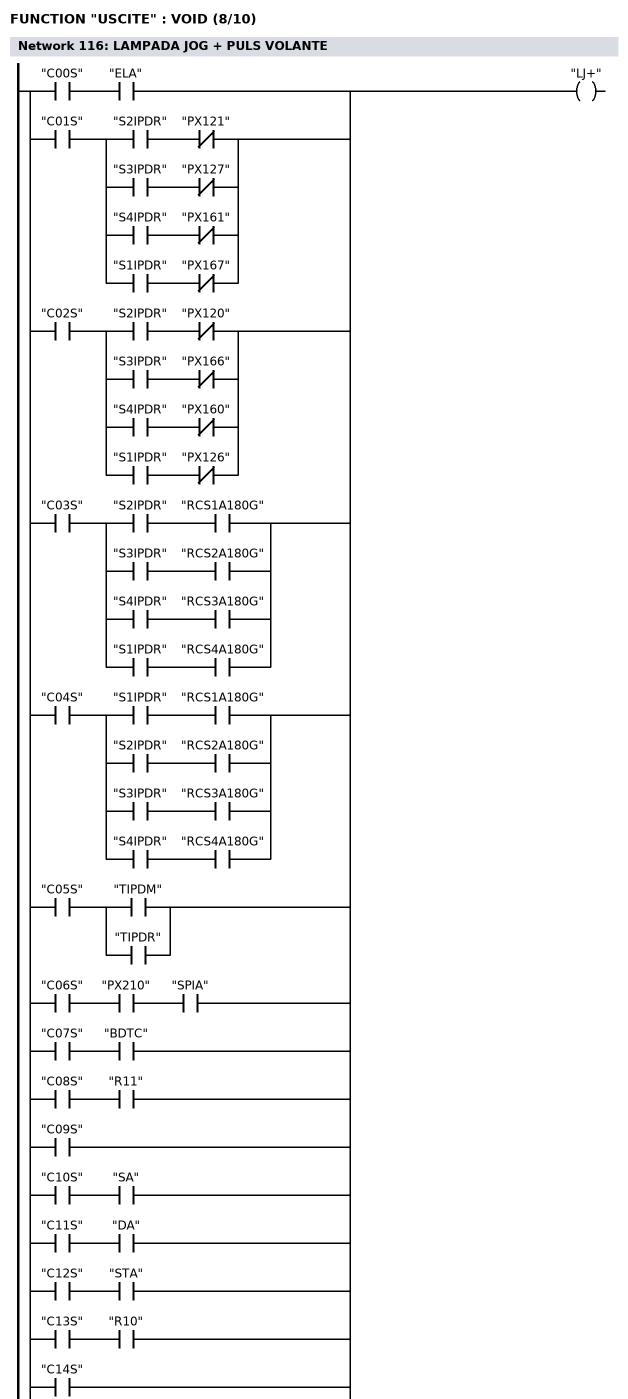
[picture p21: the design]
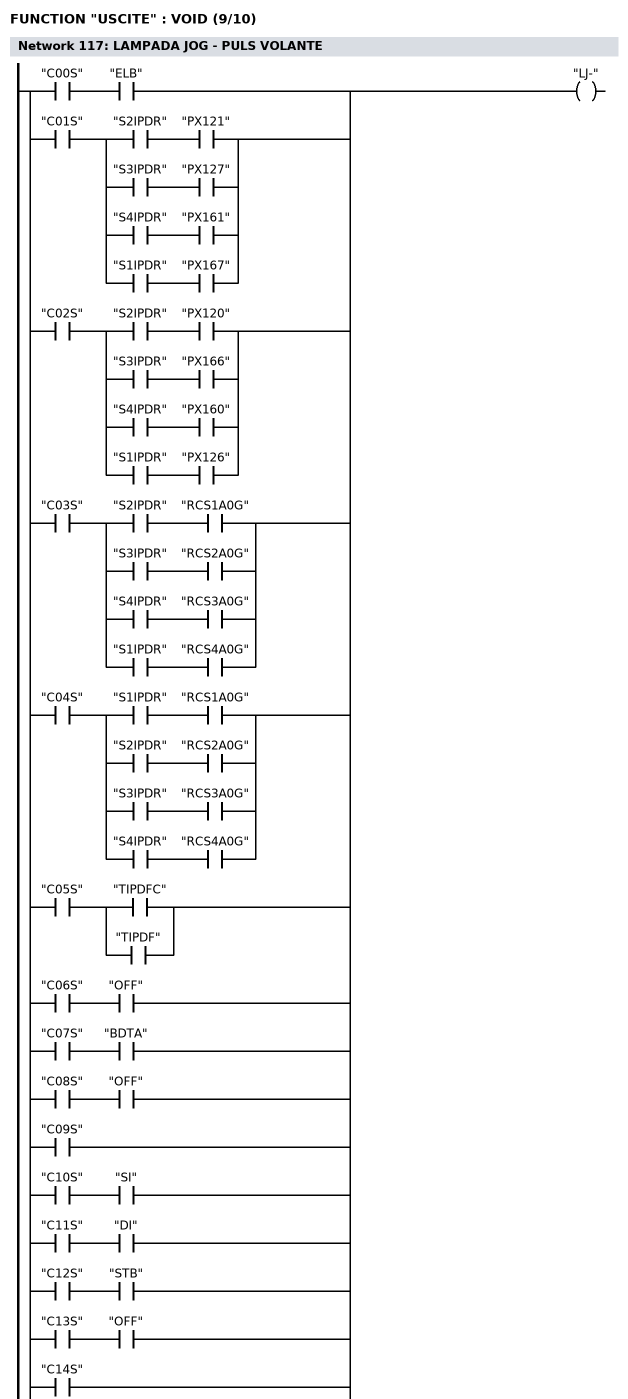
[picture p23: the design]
FUNCTION "USCITE" : VOID
TITLE =USCITE
VERSION : 0.1

BEGIN
NETWORK
TITLE =MARCIA GENERALE

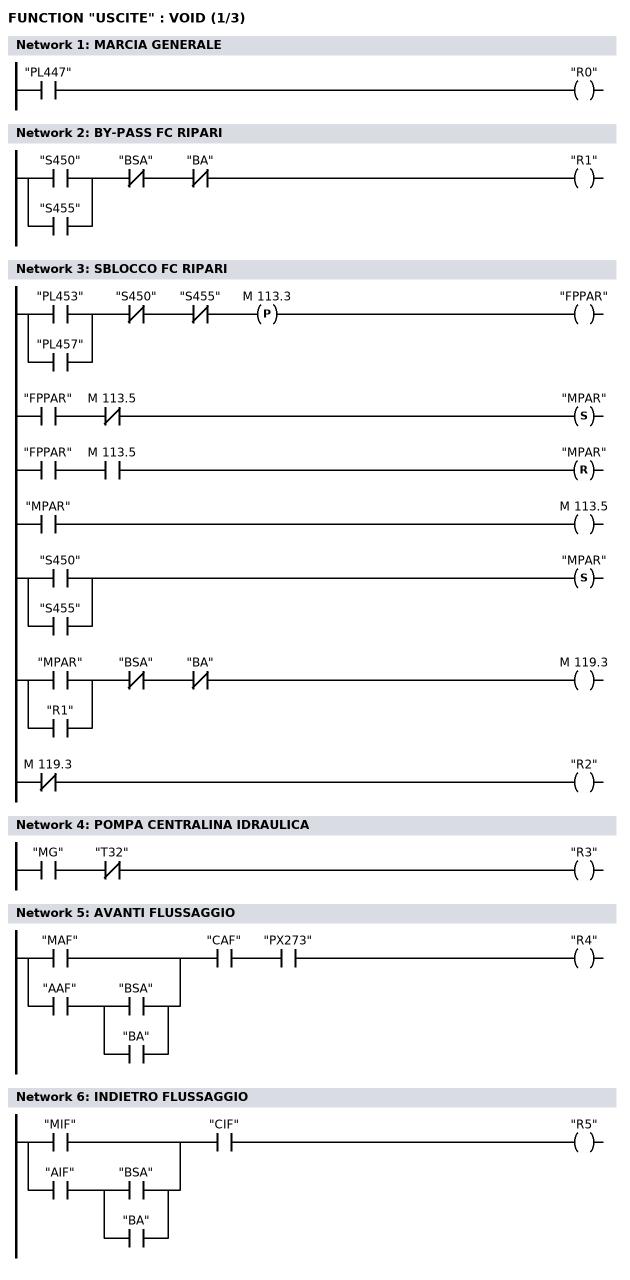
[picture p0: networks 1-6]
      U     "PL447";
      =     "R0";
NETWORK
TITLE =BY-PASS FC RIPARI

      U(    ;
      O     "S450";
      O     "S455";
      )     ;
      UN    "BSA";
      UN    "BA";
      =     "R1";
NETWORK
TITLE =SBLOCCO FC RIPARI

      U(    ;
      U     "PL453";
      O     ;
      U     "PL457";
      )     ;
      UN    "S450";
      UN    "S455";
      FP    M    113.3;
      =     "FPPAR";

      U     "FPPAR";
      UN    M    113.5;
      S     "MPAR";

      U     "FPPAR";
      U     M    113.5;
      R     "MPAR";

      U     "MPAR";
      =     M    113.5;

      U     "S450";
      O     "S455";
      S     "MPAR";

      U(    ;
      U     "MPAR";
      O     ;
      U     "R1";
      )     ;
      UN    "BSA";
      UN    "BA";
      =     M    119.3;
      UN    M    119.3;
      =     "R2";
NETWORK
TITLE =POMPA CENTRALINA IDRAULICA

      U     "MG";
      UN    "T32";
      =     "R3";
NETWORK
TITLE =AVANTI FLUSSAGGIO

      U(    ;
      O     "MAF";
      O     ;
      U     "AAF";
      U(    ;
      O     "BSA";
      O     "BA";
      )     ;
      )     ;
      U     "CAF";
      U     "PX273";
      =     "R4";
NETWORK
TITLE =INDIETRO FLUSSAGGIO

      U(    ;
      O     "MIF";
      O     ;
      U     "AIF";
      U(    ;
      O     "BSA";
      O     "BA";
      )     ;
      )     ;
      U     "CIF";
      =     "R5";
NETWORK
TITLE =AVANTI SPAZZOLATURA

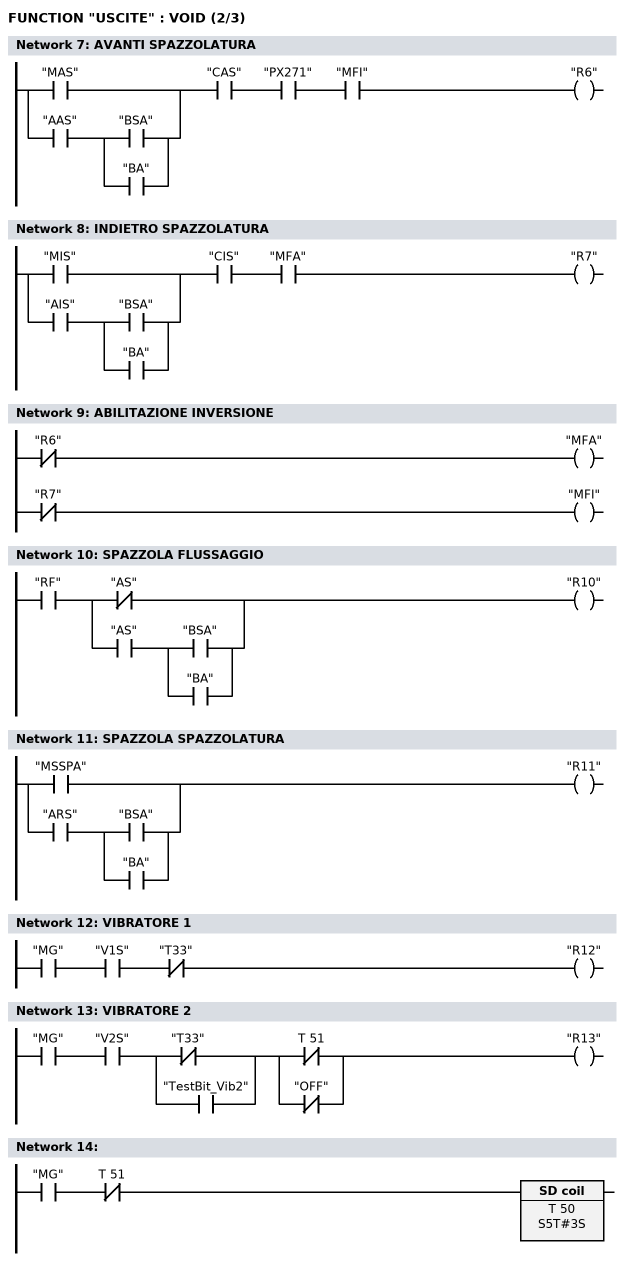
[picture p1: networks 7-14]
      U(    ;
      O     "MAS";
      O     ;
      U     "AAS";
      U(    ;
      O     "BSA";
      O     "BA";
      )     ;
      )     ;
      U     "CAS";
      U     "PX271";
      U     "MFI";
      =     "R6";
NETWORK
TITLE =INDIETRO SPAZZOLATURA

      U(    ;
      O     "MIS";
      O     ;
      U     "AIS";
      U(    ;
      O     "BSA";
      O     "BA";
      )     ;
      )     ;
      U     "CIS";
      U     "MFA";
      =     "R7";
NETWORK
TITLE =ABILITAZIONE INVERSIONE

      UN    "R6";
      =     "MFA";

      UN    "R7";
      =     "MFI";
NETWORK
TITLE =SPAZZOLA FLUSSAGGIO

      U     "RF";
      U(    ;
      ON    "AS";
      O     ;
      U     "AS";
      U(    ;
      O     "BSA";
      O     "BA";
      )     ;
      )     ;
      =     "R10";
NETWORK
TITLE =SPAZZOLA SPAZZOLATURA

      O     "MSSPA";
      O     ;
      U     "ARS";
      U(    ;
      O     "BSA";
      O     "BA";
      )     ;
      =     "R11";
NETWORK
TITLE =VIBRATORE 1

      U     "MG";
      U     "V1S";
      UN    "T33";
      =     "R12";
NETWORK
TITLE =VIBRATORE 2

      U     "MG";
      U     "V2S";
      U(    ;
      ON    "T33";
      O     "TestBit_Vib2";
      )     ;
      U(    ;
      ON    T     51;
      ON    "OFF";
      )     ;
      =     "R13";
NETWORK
TITLE =

      U     "MG";
      UN    T     51;
      L     S5T#3S;
      SE    T     50;
NETWORK
TITLE =

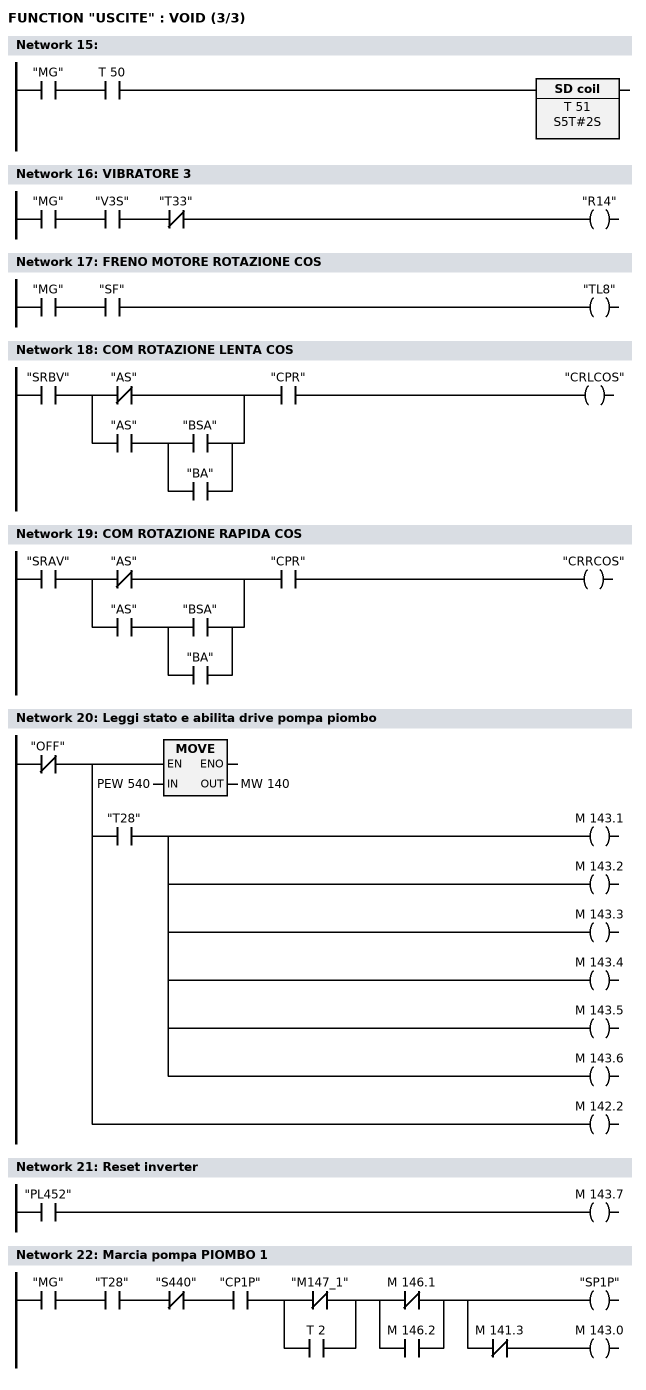
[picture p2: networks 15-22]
      U     "MG";
      U     T     50;
      L     S5T#2S;
      SE    T     51;
NETWORK
TITLE =VIBRATORE 3

      U     "MG";
      U     "V3S";
      UN    "T33";
      =     "R14";
NETWORK
TITLE =FRENO MOTORE ROTAZIONE COS

      U     "MG";
      U     "SF";
      =     "TL8";
NETWORK
TITLE =COM ROTAZIONE LENTA COS

      U     "SRBV";
      U(    ;
      ON    "AS";
      O     ;
      U     "AS";
      U(    ;
      O     "BSA";
      O     "BA";
      )     ;
      )     ;
      U     "CPR";
      =     "CRLCOS";
NETWORK
TITLE =COM ROTAZIONE RAPIDA COS

      U     "SRAV";
      U(    ;
      ON    "AS";
      O     ;
      U     "AS";
      U(    ;
      O     "BSA";
      O     "BA";
      )     ;
      )     ;
      U     "CPR";
      =     "CRRCOS";
NETWORK
TITLE =Leggi stato e abilita drive pompa piombo

      UN    "OFF";
      =     L      0.0;
      U     L      0.0;
      SPBNB _001;
      L     PEW  540;
      T     MW   140;
_001: NOP   0;
      U     L      0.0;
      U     "T28";
      =     M    143.1;
      =     M    143.2;
      =     M    143.3;
      =     M    143.4;
      =     M    143.5;
      =     M    143.6;
      U     L      0.0;
      BLD   102;
      =     M    142.2;
NETWORK
TITLE =Reset inverter

      U     "PL452";
      =     M    143.7;
NETWORK
TITLE =Marcia pompa PIOMBO 1

      U     "MG";
      U     "T28";
      UN    "S440";
      U     "CP1P";
      U(    ;
      ON    "M147_1";
      O     T      2;
      )     ;
      U(    ;
      ON    M    146.1;
      O     M    146.2;
      )     ;
      =     L      0.0;
      U     L      0.0;
      BLD   102;
      =     "SP1P";
      U     L      0.0;
      UN    M    141.3;
      =     M    143.0;
NETWORK
TITLE =Velocita pompa piombo
//Sul ramo di alta velocità della pompa è stato inserita la possibilità di un
//offset (default=0)
      U     "SP1P";
      =     L      0.0;
      U     L      0.0;
      UN    "R43";
      SPBNB _002;
      L     DB32.DBW    0;
      L     12;
      *I    ;
      T     PAW  542;
_002: NOP   0;
      U(    ;
      U     L      0.0;
      U     "R43";
      SPBNB _003;
      L     DB32.DBW    2;
      L     0;
      +I    ;
      T     MW   134;
      UN    OV;
      SAVE  ;
      CLR   ;
_003: U     BIE;
      )     ;
      SPBNB _004;
      L     MW   134;
      L     12;
      *I    ;
      T     PAW  542;
_004: NOP   0;
      U     L      0.0;
      NOT   ;
      SPBNB _005;
      L     0;
      T     PAW  542;
_005: NOP   0;
NETWORK
TITLE =Scrivi comandi pompa piombo

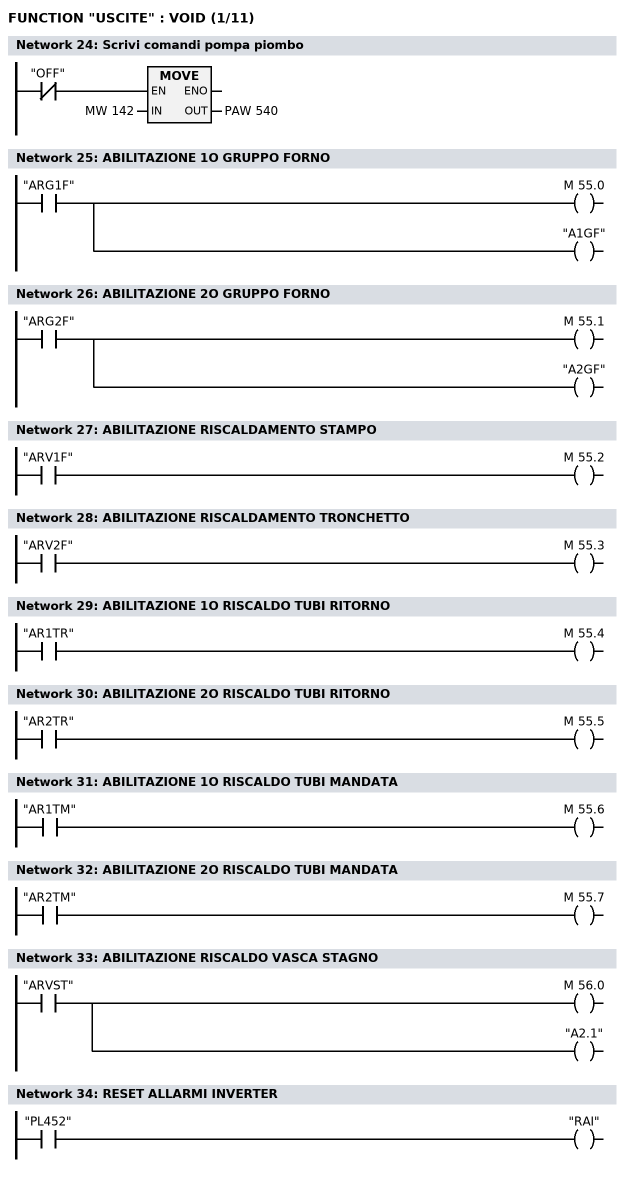
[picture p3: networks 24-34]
      UN    "OFF";
      SPBNB _006;
      L     MW   142;
      T     PAW  540;
_006: NOP   0;
NETWORK
TITLE =ABILITAZIONE 1O GRUPPO FORNO

      U     "ARG1F";
      =     M     55.0;
      =     "A1GF";
NETWORK
TITLE =ABILITAZIONE 2O GRUPPO FORNO

      U     "ARG2F";
      =     M     55.1;
      =     "A2GF";
NETWORK
TITLE =ABILITAZIONE RISCALDAMENTO STAMPO

      U     "ARV1F";
      =     M     55.2;
NETWORK
TITLE =ABILITAZIONE RISCALDAMENTO TRONCHETTO

      U     "ARV2F";
      =     M     55.3;
NETWORK
TITLE =ABILITAZIONE 1O RISCALDO TUBI RITORNO

      U     "AR1TR";
      =     M     55.4;
NETWORK
TITLE =ABILITAZIONE 2O RISCALDO TUBI RITORNO

      U     "AR2TR";
      =     M     55.5;
NETWORK
TITLE =ABILITAZIONE 1O RISCALDO TUBI MANDATA

      U     "AR1TM";
      =     M     55.6;
NETWORK
TITLE =ABILITAZIONE 2O RISCALDO TUBI MANDATA

      U     "AR2TM";
      =     M     55.7;
NETWORK
TITLE =ABILITAZIONE RISCALDO VASCA STAGNO

      U     "ARVST";
      =     M     56.0;
      =     "A2.1";
NETWORK
TITLE =RESET ALLARMI INVERTER

      U     "PL452";
      =     "RAI";
NETWORK
TITLE =MEM ABILITAZIONE ASSI

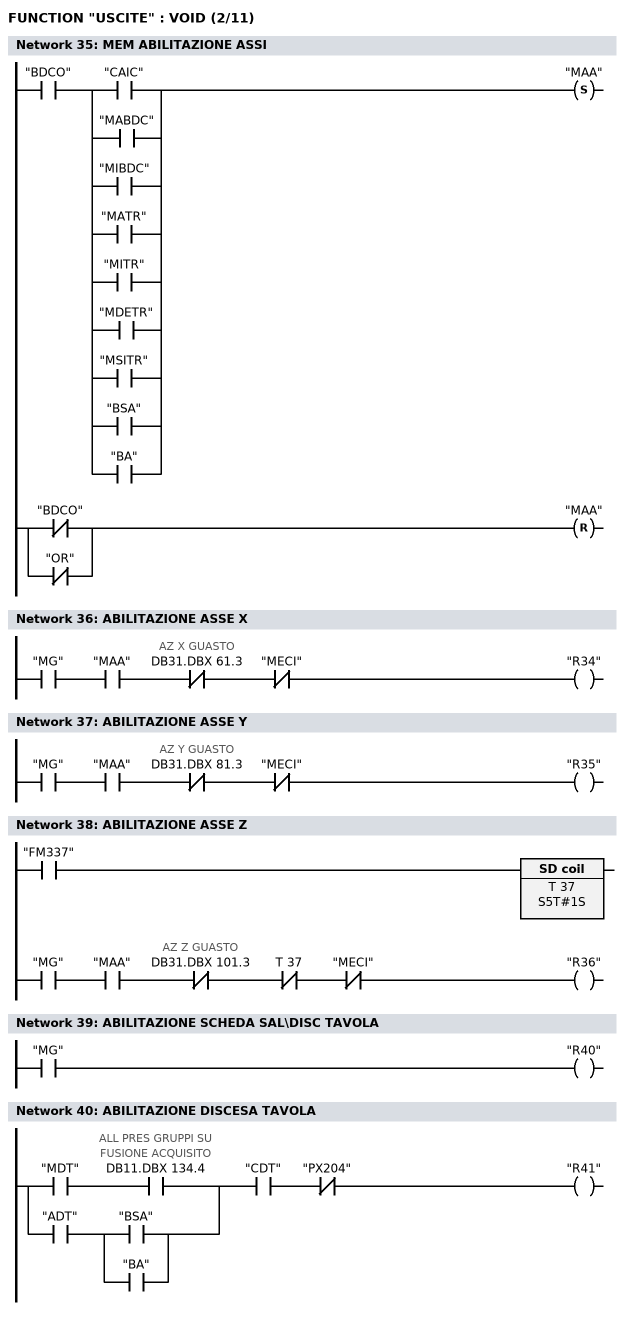
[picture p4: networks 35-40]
      U     "BDCO";
      U(    ;
      U     "CAIC";
      O     "MABDC";
      O     "MIBDC";
      O     "MATR";
      O     "MITR";
      O     "MDETR";
      O     "MSITR";
      O     "BSA";
      O     "BA";
      )     ;
      S     "MAA";

      UN    "BDCO";
      ON    "OR";
      R     "MAA";
NETWORK
TITLE =ABILITAZIONE ASSE X

      U     "MG";
      U     "MAA";
      UN    DB31.DBX   61.3; // AZ X GUASTO
      UN    "MECI";
      =     "R34";
NETWORK
TITLE =ABILITAZIONE ASSE Y

      U     "MG";
      U     "MAA";
      UN    DB31.DBX   81.3; // AZ Y GUASTO
      UN    "MECI";
      =     "R35";
NETWORK
TITLE =ABILITAZIONE ASSE Z

      U     "FM337";
      L     S5T#1S;
      SE    T     37;

      U     "MG";
      U     "MAA";
      UN    DB31.DBX  101.3; // AZ Z GUASTO
      UN    T     37;
      UN    "MECI";
      =     "R36";
NETWORK
TITLE =ABILITAZIONE SCHEDA SAL\DISC TAVOLA

      U     "MG";
      =     "R40";
NETWORK
TITLE =ABILITAZIONE DISCESA TAVOLA

      U(    ;
      U     "MDT";
      U     DB11.DBX  134.4; // ALL PRES GRUPPI SU FUSIONE ACQUISITO
      O     ;
      U     "ADT";
      U(    ;
      O     "BSA";
      O     "BA";
      )     ;
      )     ;
      U     "CDT";
      UN    "PX204";
      =     "R41";
NETWORK
TITLE =ABILITAZIONE SALITA TAVOLA

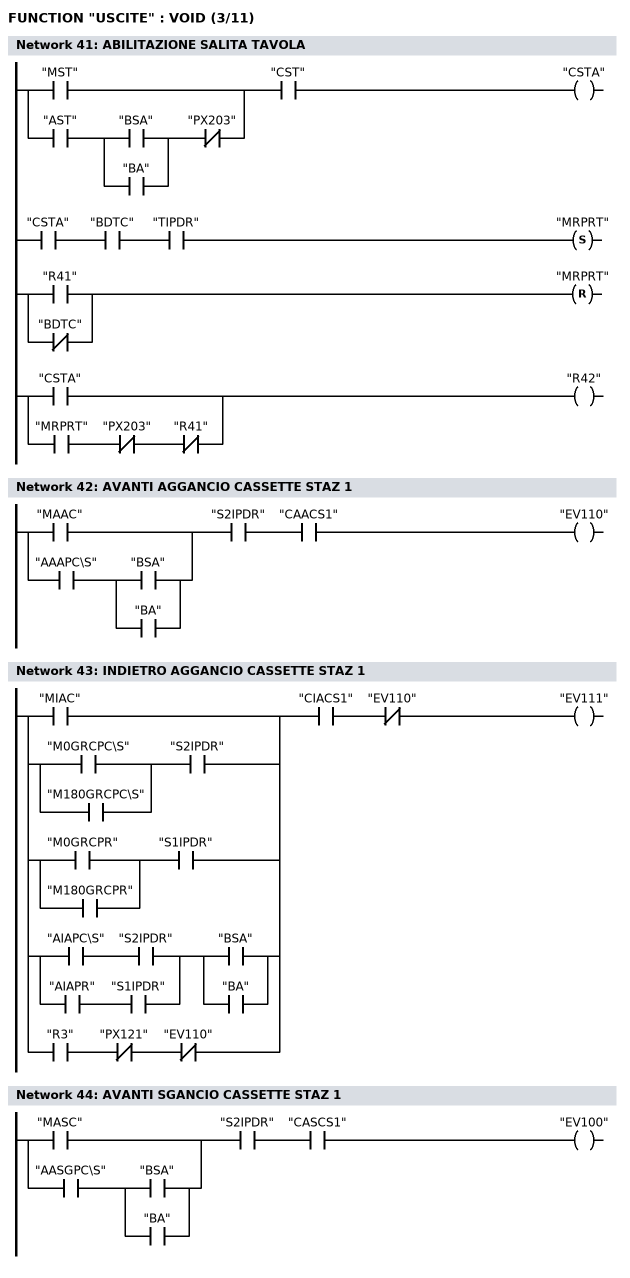
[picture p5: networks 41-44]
      U(    ;
      U     "MST";
      O     ;
      U     "AST";
      U(    ;
      U     "BSA";
      O     "BA";
      )     ;
      UN    "PX203";
      )     ;
      U     "CST";
      =     "CSTA";

      U     "CSTA";
      U     "BDTC";
      U     "TIPDR";
      S     "MRPRT";

      U     "R41";
      ON    "BDTC";
      R     "MRPRT";

      U     "CSTA";
      O     ;
      U     "MRPRT";
      UN    "PX203";
      UN    "R41";
      =     "R42";
NETWORK
TITLE =AVANTI AGGANCIO CASSETTE STAZ 1

      U(    ;
      O     "MAAC";
      O     ;
      U     "AAAPC\S";
      U(    ;
      O     "BSA";
      O     "BA";
      )     ;
      )     ;
      U     "S2IPDR";
      U     "CAACS1";
      =     "EV110";
NETWORK
TITLE =INDIETRO AGGANCIO CASSETTE STAZ 1

      U(    ;
      O     "MIAC";
      O     ;
      U(    ;
      O     "M0GRCPC\S";
      O     "M180GRCPC\S";
      )     ;
      U     "S2IPDR";
      O     ;
      U(    ;
      O     "M0GRCPR";
      O     "M180GRCPR";
      )     ;
      U     "S1IPDR";
      O     ;
      U(    ;
      U     "AIAPC\S";
      U     "S2IPDR";
      O     ;
      U     "AIAPR";
      U     "S1IPDR";
      )     ;
      U(    ;
      O     "BSA";
      O     "BA";
      )     ;
      O     ;
      U     "R3";
      UN    "PX121";
      UN    "EV110";
      )     ;
      U     "CIACS1";
      UN    "EV110";
      =     "EV111";
NETWORK
TITLE =AVANTI SGANCIO CASSETTE STAZ 1

      U(    ;
      O     "MASC";
      O     ;
      U     "AASGPC\S";
      U(    ;
      O     "BSA";
      O     "BA";
      )     ;
      )     ;
      U     "S2IPDR";
      U     "CASCS1";
      =     "EV100";
NETWORK
TITLE =INDIETRO SGANCIO CASSETTE STAZ 1

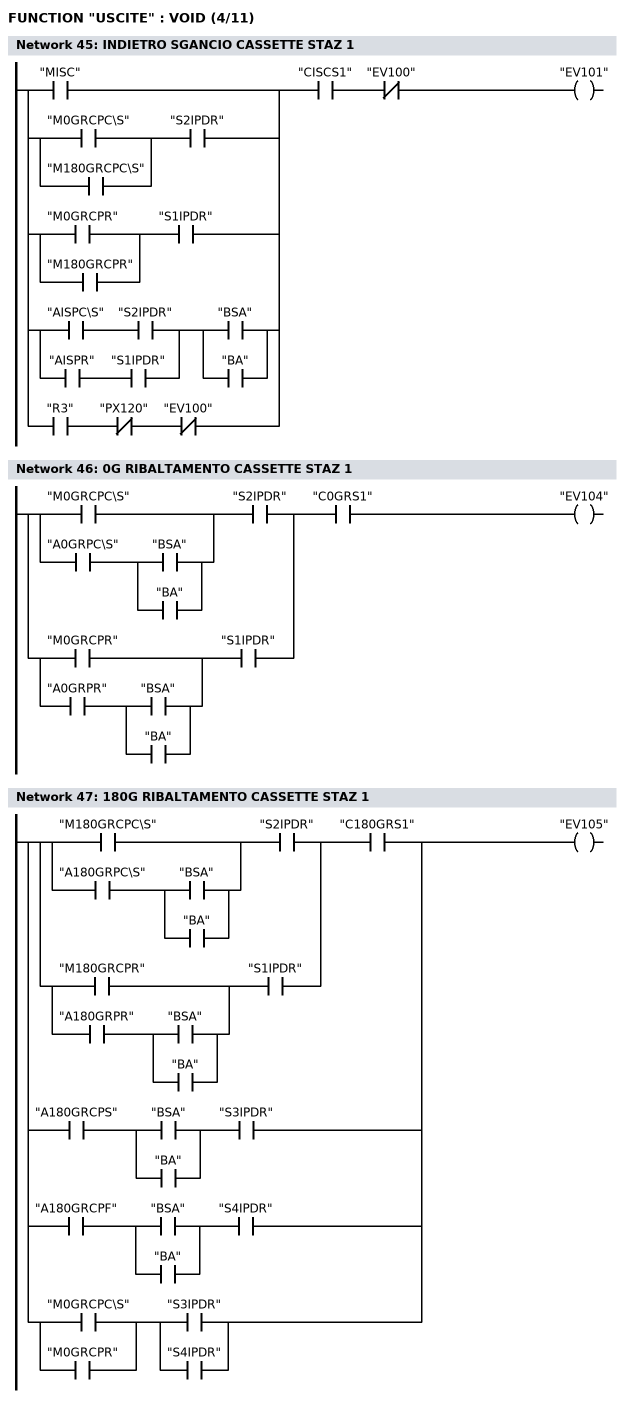
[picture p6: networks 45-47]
      U(    ;
      O     "MISC";
      O     ;
      U(    ;
      O     "M0GRCPC\S";
      O     "M180GRCPC\S";
      )     ;
      U     "S2IPDR";
      O     ;
      U(    ;
      O     "M0GRCPR";
      O     "M180GRCPR";
      )     ;
      U     "S1IPDR";
      O     ;
      U(    ;
      U     "AISPC\S";
      U     "S2IPDR";
      O     ;
      U     "AISPR";
      U     "S1IPDR";
      )     ;
      U(    ;
      O     "BSA";
      O     "BA";
      )     ;
      O     ;
      U     "R3";
      UN    "PX120";
      UN    "EV100";
      )     ;
      U     "CISCS1";
      UN    "EV100";
      =     "EV101";
NETWORK
TITLE =0G RIBALTAMENTO CASSETTE STAZ 1

      U(    ;
      U(    ;
      O     "M0GRCPC\S";
      O     ;
      U     "A0GRPC\S";
      U(    ;
      O     "BSA";
      O     "BA";
      )     ;
      )     ;
      U     "S2IPDR";
      O     ;
      U(    ;
      O     "M0GRCPR";
      O     ;
      U     "A0GRPR";
      U(    ;
      O     "BSA";
      O     "BA";
      )     ;
      )     ;
      U     "S1IPDR";
      )     ;
      U     "C0GRS1";
      =     "EV104";
NETWORK
TITLE =180G RIBALTAMENTO CASSETTE STAZ 1

      U(    ;
      U(    ;
      O     "M180GRCPC\S";
      O     ;
      U     "A180GRPC\S";
      U(    ;
      O     "BSA";
      O     "BA";
      )     ;
      )     ;
      U     "S2IPDR";
      O     ;
      U(    ;
      O     "M180GRCPR";
      O     ;
      U     "A180GRPR";
      U(    ;
      O     "BSA";
      O     "BA";
      )     ;
      )     ;
      U     "S1IPDR";
      )     ;
      U     "C180GRS1";
      O     ;
      U     "A180GRCPS";
      U(    ;
      O     "BSA";
      O     "BA";
      )     ;
      U     "S3IPDR";
      O     ;
      U     "A180GRCPF";
      U(    ;
      O     "BSA";
      O     "BA";
      )     ;
      U     "S4IPDR";
      O     ;
      U(    ;
      O     "M0GRCPC\S";
      O     "M0GRCPR";
      )     ;
      U(    ;
      O     "S3IPDR";
      O     "S4IPDR";
      )     ;
      =     "EV105";
NETWORK
TITLE =AVANTI AGGANCIO CASSETTE STAZ 2

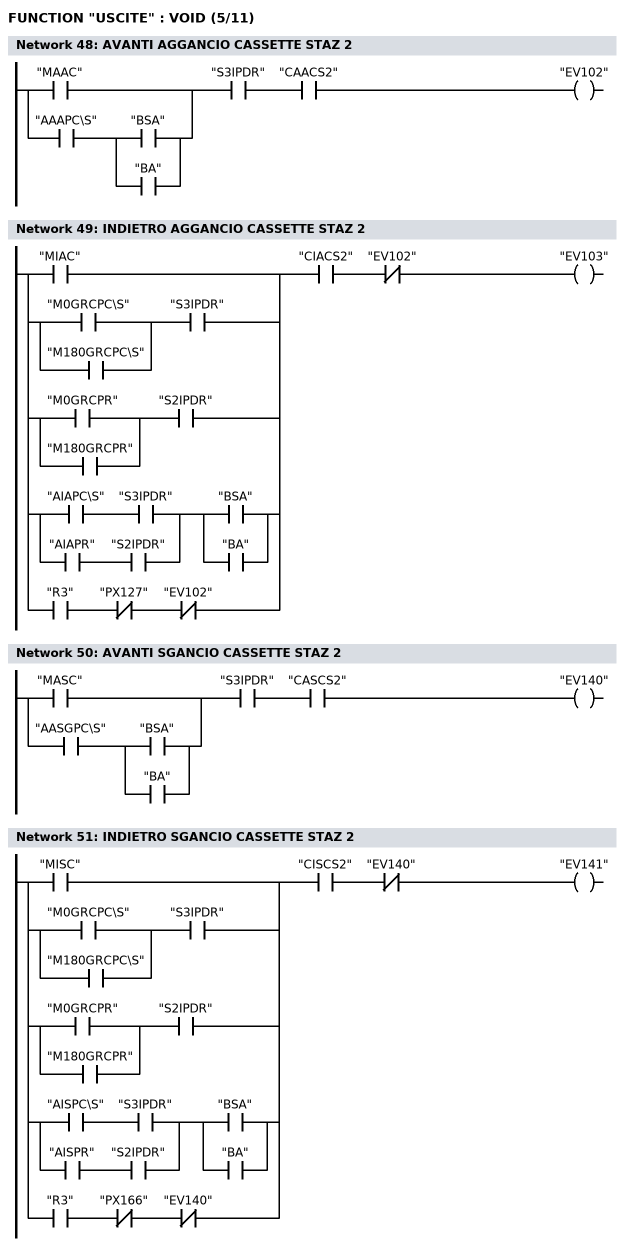
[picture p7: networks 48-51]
      U(    ;
      O     "MAAC";
      O     ;
      U     "AAAPC\S";
      U(    ;
      O     "BSA";
      O     "BA";
      )     ;
      )     ;
      U     "S3IPDR";
      U     "CAACS2";
      =     "EV102";
NETWORK
TITLE =INDIETRO AGGANCIO CASSETTE STAZ 2

      U(    ;
      O     "MIAC";
      O     ;
      U(    ;
      O     "M0GRCPC\S";
      O     "M180GRCPC\S";
      )     ;
      U     "S3IPDR";
      O     ;
      U(    ;
      O     "M0GRCPR";
      O     "M180GRCPR";
      )     ;
      U     "S2IPDR";
      O     ;
      U(    ;
      U     "AIAPC\S";
      U     "S3IPDR";
      O     ;
      U     "AIAPR";
      U     "S2IPDR";
      )     ;
      U(    ;
      O     "BSA";
      O     "BA";
      )     ;
      O     ;
      U     "R3";
      UN    "PX127";
      UN    "EV102";
      )     ;
      U     "CIACS2";
      UN    "EV102";
      =     "EV103";
NETWORK
TITLE =AVANTI SGANCIO CASSETTE STAZ 2

      U(    ;
      O     "MASC";
      O     ;
      U     "AASGPC\S";
      U(    ;
      O     "BSA";
      O     "BA";
      )     ;
      )     ;
      U     "S3IPDR";
      U     "CASCS2";
      =     "EV140";
NETWORK
TITLE =INDIETRO SGANCIO CASSETTE STAZ 2

      U(    ;
      O     "MISC";
      O     ;
      U(    ;
      O     "M0GRCPC\S";
      O     "M180GRCPC\S";
      )     ;
      U     "S3IPDR";
      O     ;
      U(    ;
      O     "M0GRCPR";
      O     "M180GRCPR";
      )     ;
      U     "S2IPDR";
      O     ;
      U(    ;
      U     "AISPC\S";
      U     "S3IPDR";
      O     ;
      U     "AISPR";
      U     "S2IPDR";
      )     ;
      U(    ;
      O     "BSA";
      O     "BA";
      )     ;
      O     ;
      U     "R3";
      UN    "PX166";
      UN    "EV140";
      )     ;
      U     "CISCS2";
      UN    "EV140";
      =     "EV141";
NETWORK
TITLE =0G RIBALTAMENTO CASSETTE STAZ 2

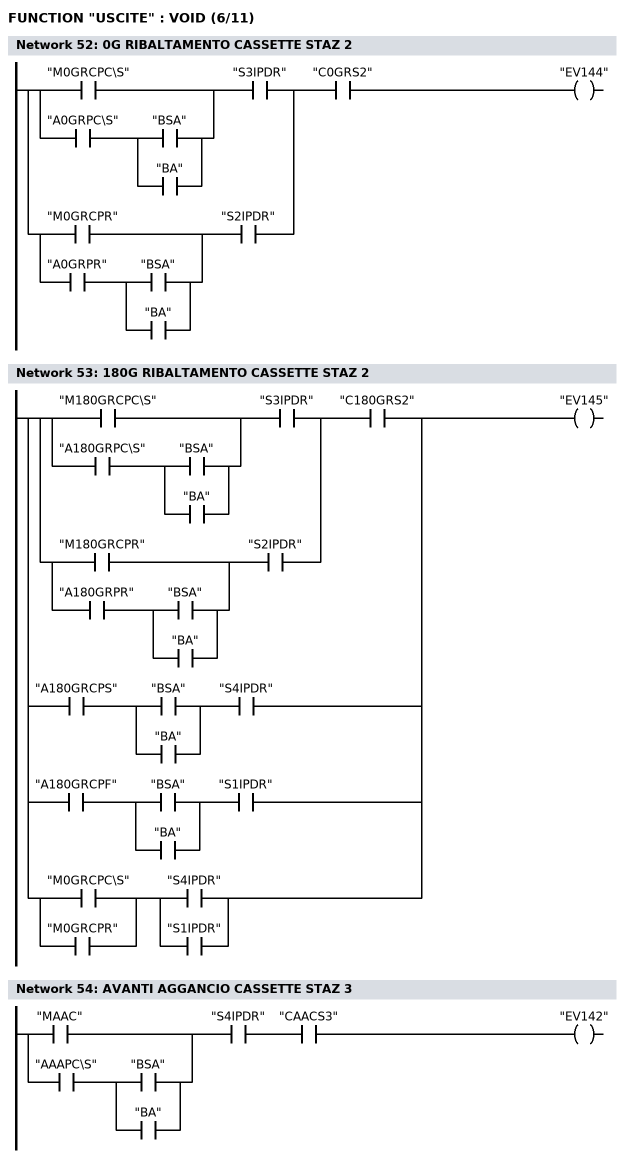
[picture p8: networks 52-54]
      U(    ;
      U(    ;
      O     "M0GRCPC\S";
      O     ;
      U     "A0GRPC\S";
      U(    ;
      O     "BSA";
      O     "BA";
      )     ;
      )     ;
      U     "S3IPDR";
      O     ;
      U(    ;
      O     "M0GRCPR";
      O     ;
      U     "A0GRPR";
      U(    ;
      O     "BSA";
      O     "BA";
      )     ;
      )     ;
      U     "S2IPDR";
      )     ;
      U     "C0GRS2";
      =     "EV144";
NETWORK
TITLE =180G RIBALTAMENTO CASSETTE STAZ 2

      U(    ;
      U(    ;
      O     "M180GRCPC\S";
      O     ;
      U     "A180GRPC\S";
      U(    ;
      O     "BSA";
      O     "BA";
      )     ;
      )     ;
      U     "S3IPDR";
      O     ;
      U(    ;
      O     "M180GRCPR";
      O     ;
      U     "A180GRPR";
      U(    ;
      O     "BSA";
      O     "BA";
      )     ;
      )     ;
      U     "S2IPDR";
      )     ;
      U     "C180GRS2";
      O     ;
      U     "A180GRCPS";
      U(    ;
      O     "BSA";
      O     "BA";
      )     ;
      U     "S4IPDR";
      O     ;
      U     "A180GRCPF";
      U(    ;
      O     "BSA";
      O     "BA";
      )     ;
      U     "S1IPDR";
      O     ;
      U(    ;
      O     "M0GRCPC\S";
      O     "M0GRCPR";
      )     ;
      U(    ;
      O     "S4IPDR";
      O     "S1IPDR";
      )     ;
      =     "EV145";
NETWORK
TITLE =AVANTI AGGANCIO CASSETTE STAZ 3

      U(    ;
      O     "MAAC";
      O     ;
      U     "AAAPC\S";
      U(    ;
      O     "BSA";
      O     "BA";
      )     ;
      )     ;
      U     "S4IPDR";
      U     "CAACS3";
      =     "EV142";
NETWORK
TITLE =INDIETRO AGGANCIO CASSETTE STAZ 3

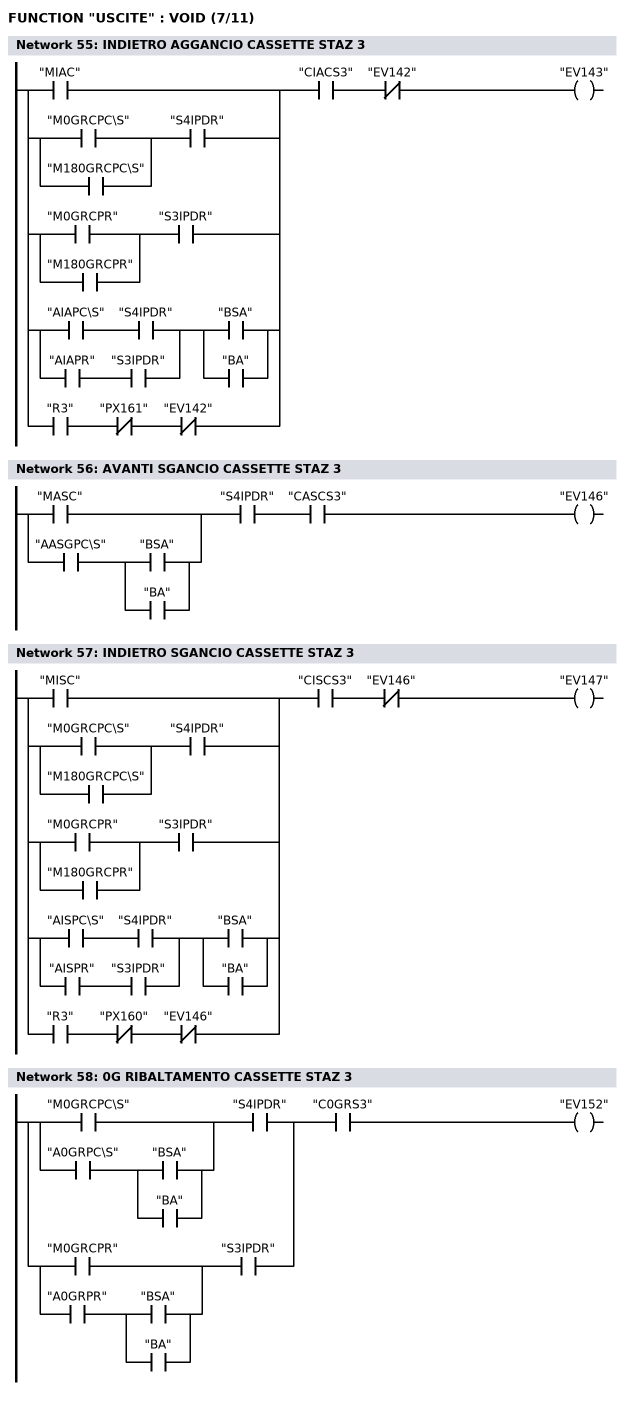
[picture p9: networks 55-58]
      U(    ;
      O     "MIAC";
      O     ;
      U(    ;
      O     "M0GRCPC\S";
      O     "M180GRCPC\S";
      )     ;
      U     "S4IPDR";
      O     ;
      U(    ;
      O     "M0GRCPR";
      O     "M180GRCPR";
      )     ;
      U     "S3IPDR";
      O     ;
      U(    ;
      U     "AIAPC\S";
      U     "S4IPDR";
      O     ;
      U     "AIAPR";
      U     "S3IPDR";
      )     ;
      U(    ;
      O     "BSA";
      O     "BA";
      )     ;
      O     ;
      U     "R3";
      UN    "PX161";
      UN    "EV142";
      )     ;
      U     "CIACS3";
      UN    "EV142";
      =     "EV143";
NETWORK
TITLE =AVANTI SGANCIO CASSETTE STAZ 3

      U(    ;
      O     "MASC";
      O     ;
      U     "AASGPC\S";
      U(    ;
      O     "BSA";
      O     "BA";
      )     ;
      )     ;
      U     "S4IPDR";
      U     "CASCS3";
      =     "EV146";
NETWORK
TITLE =INDIETRO SGANCIO CASSETTE STAZ 3

      U(    ;
      O     "MISC";
      O     ;
      U(    ;
      O     "M0GRCPC\S";
      O     "M180GRCPC\S";
      )     ;
      U     "S4IPDR";
      O     ;
      U(    ;
      O     "M0GRCPR";
      O     "M180GRCPR";
      )     ;
      U     "S3IPDR";
      O     ;
      U(    ;
      U     "AISPC\S";
      U     "S4IPDR";
      O     ;
      U     "AISPR";
      U     "S3IPDR";
      )     ;
      U(    ;
      O     "BSA";
      O     "BA";
      )     ;
      O     ;
      U     "R3";
      UN    "PX160";
      UN    "EV146";
      )     ;
      U     "CISCS3";
      UN    "EV146";
      =     "EV147";
NETWORK
TITLE =0G RIBALTAMENTO CASSETTE STAZ 3

      U(    ;
      U(    ;
      O     "M0GRCPC\S";
      O     ;
      U     "A0GRPC\S";
      U(    ;
      O     "BSA";
      O     "BA";
      )     ;
      )     ;
      U     "S4IPDR";
      O     ;
      U(    ;
      O     "M0GRCPR";
      O     ;
      U     "A0GRPR";
      U(    ;
      O     "BSA";
      O     "BA";
      )     ;
      )     ;
      U     "S3IPDR";
      )     ;
      U     "C0GRS3";
      =     "EV152";
NETWORK
TITLE =180G RIBALTAMENTO CASSETTE STAZ 3

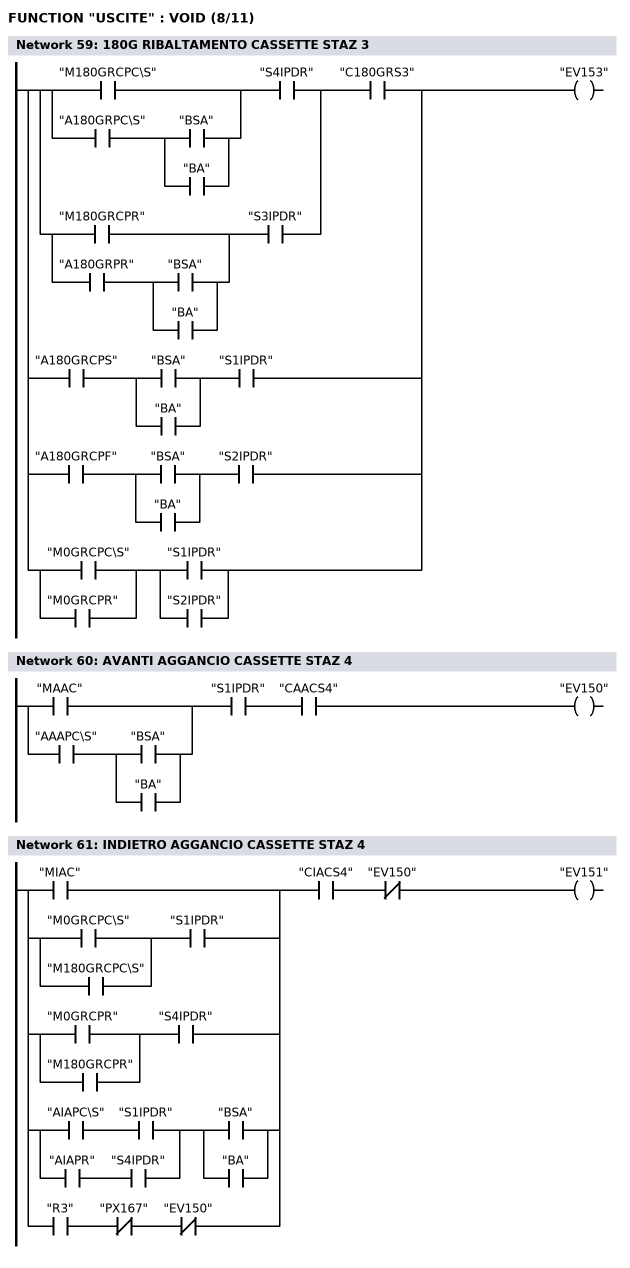
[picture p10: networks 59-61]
      U(    ;
      U(    ;
      O     "M180GRCPC\S";
      O     ;
      U     "A180GRPC\S";
      U(    ;
      O     "BSA";
      O     "BA";
      )     ;
      )     ;
      U     "S4IPDR";
      O     ;
      U(    ;
      O     "M180GRCPR";
      O     ;
      U     "A180GRPR";
      U(    ;
      O     "BSA";
      O     "BA";
      )     ;
      )     ;
      U     "S3IPDR";
      )     ;
      U     "C180GRS3";
      O     ;
      U     "A180GRCPS";
      U(    ;
      O     "BSA";
      O     "BA";
      )     ;
      U     "S1IPDR";
      O     ;
      U     "A180GRCPF";
      U(    ;
      O     "BSA";
      O     "BA";
      )     ;
      U     "S2IPDR";
      O     ;
      U(    ;
      O     "M0GRCPC\S";
      O     "M0GRCPR";
      )     ;
      U(    ;
      O     "S1IPDR";
      O     "S2IPDR";
      )     ;
      =     "EV153";
NETWORK
TITLE =AVANTI AGGANCIO CASSETTE STAZ 4

      U(    ;
      O     "MAAC";
      O     ;
      U     "AAAPC\S";
      U(    ;
      O     "BSA";
      O     "BA";
      )     ;
      )     ;
      U     "S1IPDR";
      U     "CAACS4";
      =     "EV150";
NETWORK
TITLE =INDIETRO AGGANCIO CASSETTE STAZ 4

      U(    ;
      O     "MIAC";
      O     ;
      U(    ;
      O     "M0GRCPC\S";
      O     "M180GRCPC\S";
      )     ;
      U     "S1IPDR";
      O     ;
      U(    ;
      O     "M0GRCPR";
      O     "M180GRCPR";
      )     ;
      U     "S4IPDR";
      O     ;
      U(    ;
      U     "AIAPC\S";
      U     "S1IPDR";
      O     ;
      U     "AIAPR";
      U     "S4IPDR";
      )     ;
      U(    ;
      O     "BSA";
      O     "BA";
      )     ;
      O     ;
      U     "R3";
      UN    "PX167";
      UN    "EV150";
      )     ;
      U     "CIACS4";
      UN    "EV150";
      =     "EV151";
NETWORK
TITLE =AVANTI SGANCIO CASSETTE STAZ 4

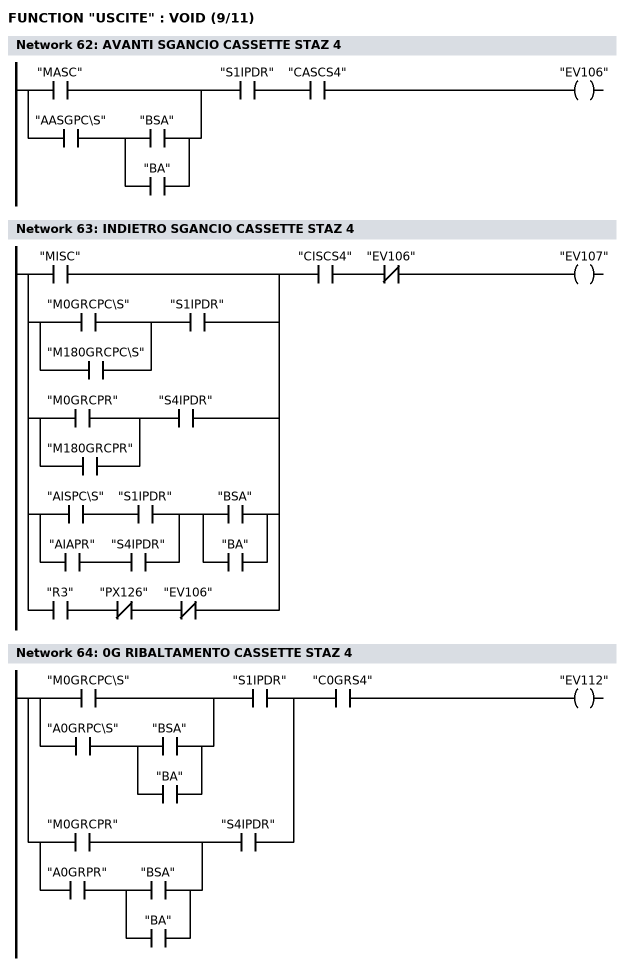
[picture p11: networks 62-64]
      U(    ;
      O     "MASC";
      O     ;
      U     "AASGPC\S";
      U(    ;
      O     "BSA";
      O     "BA";
      )     ;
      )     ;
      U     "S1IPDR";
      U     "CASCS4";
      =     "EV106";
NETWORK
TITLE =INDIETRO SGANCIO CASSETTE STAZ 4

      U(    ;
      O     "MISC";
      O     ;
      U(    ;
      O     "M0GRCPC\S";
      O     "M180GRCPC\S";
      )     ;
      U     "S1IPDR";
      O     ;
      U(    ;
      O     "M0GRCPR";
      O     "M180GRCPR";
      )     ;
      U     "S4IPDR";
      O     ;
      U(    ;
      U     "AISPC\S";
      U     "S1IPDR";
      O     ;
      U     "AIAPR";
      U     "S4IPDR";
      )     ;
      U(    ;
      O     "BSA";
      O     "BA";
      )     ;
      O     ;
      U     "R3";
      UN    "PX126";
      UN    "EV106";
      )     ;
      U     "CISCS4";
      UN    "EV106";
      =     "EV107";
NETWORK
TITLE =0G RIBALTAMENTO CASSETTE STAZ 4

      U(    ;
      U(    ;
      O     "M0GRCPC\S";
      O     ;
      U     "A0GRPC\S";
      U(    ;
      O     "BSA";
      O     "BA";
      )     ;
      )     ;
      U     "S1IPDR";
      O     ;
      U(    ;
      O     "M0GRCPR";
      O     ;
      U     "A0GRPR";
      U(    ;
      O     "BSA";
      O     "BA";
      )     ;
      )     ;
      U     "S4IPDR";
      )     ;
      U     "C0GRS4";
      =     "EV112";
NETWORK
TITLE =180G RIBALTAMENTO CASSETTE STAZ 4

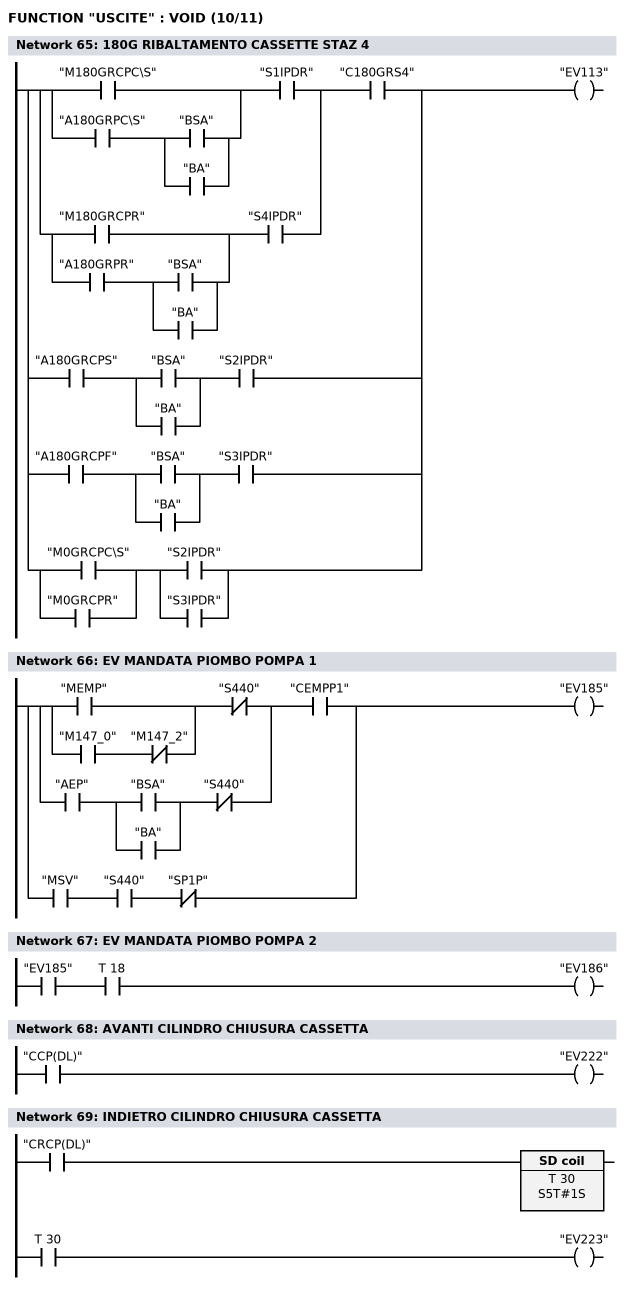
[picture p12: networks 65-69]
      U(    ;
      U(    ;
      O     "M180GRCPC\S";
      O     ;
      U     "A180GRPC\S";
      U(    ;
      O     "BSA";
      O     "BA";
      )     ;
      )     ;
      U     "S1IPDR";
      O     ;
      U(    ;
      O     "M180GRCPR";
      O     ;
      U     "A180GRPR";
      U(    ;
      O     "BSA";
      O     "BA";
      )     ;
      )     ;
      U     "S4IPDR";
      )     ;
      U     "C180GRS4";
      O     ;
      U     "A180GRCPS";
      U(    ;
      O     "BSA";
      O     "BA";
      )     ;
      U     "S2IPDR";
      O     ;
      U     "A180GRCPF";
      U(    ;
      O     "BSA";
      O     "BA";
      )     ;
      U     "S3IPDR";
      O     ;
      U(    ;
      O     "M0GRCPC\S";
      O     "M0GRCPR";
      )     ;
      U(    ;
      O     "S2IPDR";
      O     "S3IPDR";
      )     ;
      =     "EV113";
NETWORK
TITLE =EV MANDATA PIOMBO POMPA 1

      U(    ;
      U(    ;
      O     "MEMP";
      O     ;
      U     "M147_0";
      UN    "M147_2";
      )     ;
      UN    "S440";
      O     ;
      U     "AEP";
      U(    ;
      O     "BSA";
      O     "BA";
      )     ;
      UN    "S440";
      )     ;
      U     "CEMPP1";
      O     ;
      U     "MSV";
      U     "S440";
      UN    "SP1P";
      =     "EV185";
NETWORK
TITLE =EV MANDATA PIOMBO POMPA 2

      U     "EV185";
      U     T     18;
      =     "EV186";
NETWORK
TITLE =AVANTI CILINDRO CHIUSURA CASSETTA

      U     "CCP(DL)";
      =     "EV222";
NETWORK
TITLE =INDIETRO CILINDRO CHIUSURA CASSETTA

      U     "CRCP(DL)";
      L     S5T#1S;
      SE    T     30;

      U     T     30;
      =     "EV223";
NETWORK
TITLE =RALLENTAMENTO MOV.DISCESA SALITA TAVOLA COS

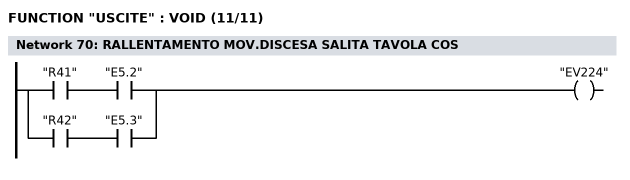
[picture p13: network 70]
      U     "R41";
      U     "E5.2";
      O     ;
      U     "R42";
      U     "E5.3";
      =     "EV224";
NETWORK
TITLE =DISCESA TAVOLA

      CLR   ;
      =     "EV225";
NETWORK
TITLE =AVANTI SPINA

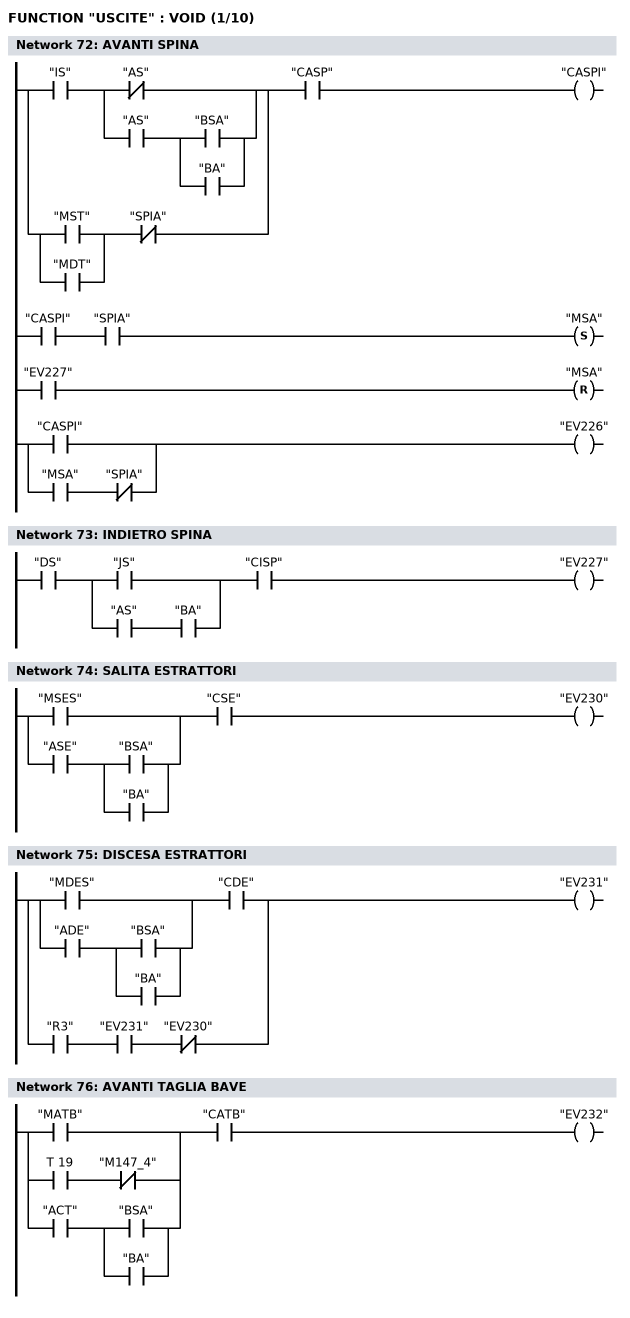
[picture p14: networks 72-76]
      U(    ;
      U     "IS";
      U(    ;
      UN    "AS";
      O     ;
      U     "AS";
      U(    ;
      U     "BSA";
      O     "BA";
      )     ;
      )     ;
      O     ;
      U(    ;
      U     "MST";
      O     "MDT";
      )     ;
      UN    "SPIA";
      )     ;
      U     "CASP";
      =     "CASPI";

      U     "CASPI";
      U     "SPIA";
      S     "MSA";

      U     "EV227";
      R     "MSA";

      U     "CASPI";
      O     ;
      U     "MSA";
      UN    "SPIA";
      =     "EV226";
NETWORK
TITLE =INDIETRO SPINA

      U     "DS";
      U(    ;
      O     "JS";
      O     ;
      U     "AS";
      U     "BA";
      )     ;
      U     "CISP";
      =     "EV227";
NETWORK
TITLE =SALITA ESTRATTORI

      U(    ;
      O     "MSES";
      O     ;
      U     "ASE";
      U(    ;
      O     "BSA";
      O     "BA";
      )     ;
      )     ;
      U     "CSE";
      =     "EV230";
NETWORK
TITLE =DISCESA ESTRATTORI

      U(    ;
      O     "MDES";
      O     ;
      U     "ADE";
      U(    ;
      O     "BSA";
      O     "BA";
      )     ;
      )     ;
      U     "CDE";
      O     ;
      U     "R3";
      U     "EV231";
      UN    "EV230";
      =     "EV231";
NETWORK
TITLE =AVANTI TAGLIA BAVE

      U(    ;
      O     "MATB";
      O     ;
      U     T     19;
      UN    "M147_4";
      O     ;
      U     "ACT";
      U(    ;
      O     "BSA";
      O     "BA";
      )     ;
      )     ;
      U     "CATB";
      =     "EV232";
NETWORK
TITLE =INDIETRO TAGLIA BAVE

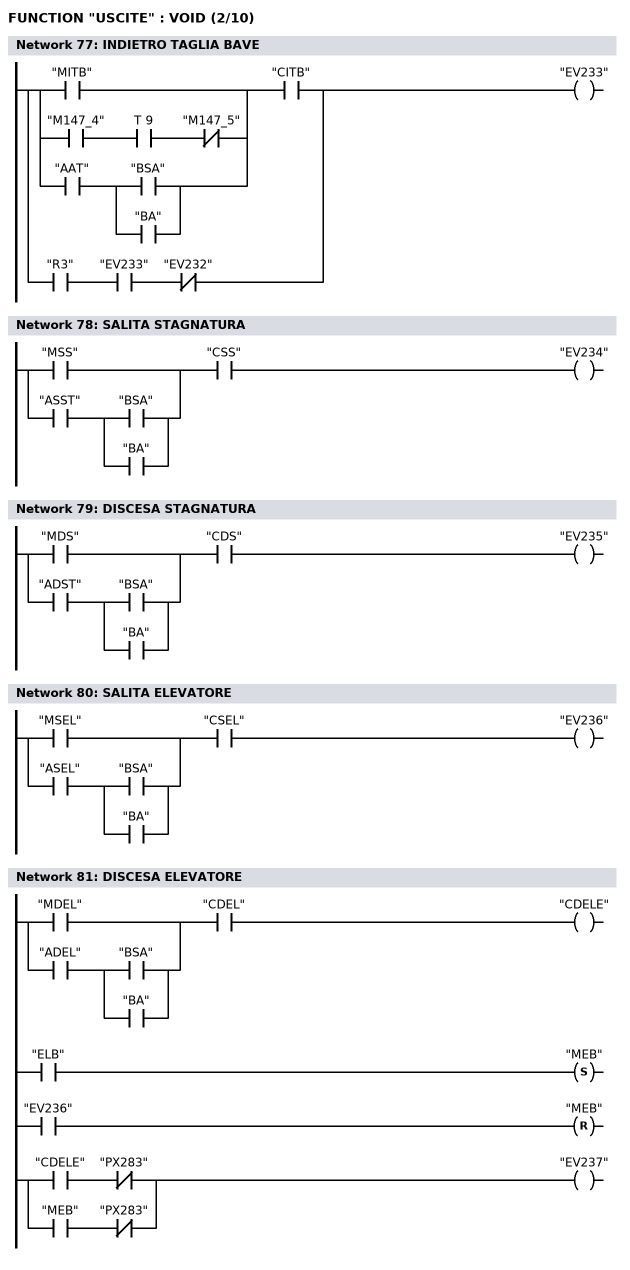
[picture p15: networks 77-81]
      U(    ;
      O     "MITB";
      O     ;
      U     "M147_4";
      U     T      9;
      UN    "M147_5";
      O     ;
      U     "AAT";
      U(    ;
      O     "BSA";
      O     "BA";
      )     ;
      )     ;
      U     "CITB";
      O     ;
      U     "R3";
      U     "EV233";
      UN    "EV232";
      =     "EV233";
NETWORK
TITLE =SALITA STAGNATURA

      U(    ;
      O     "MSS";
      O     ;
      U     "ASST";
      U(    ;
      O     "BSA";
      O     "BA";
      )     ;
      )     ;
      U     "CSS";
      =     "EV234";
NETWORK
TITLE =DISCESA STAGNATURA

      U(    ;
      O     "MDS";
      O     ;
      U     "ADST";
      U(    ;
      O     "BSA";
      O     "BA";
      )     ;
      )     ;
      U     "CDS";
      =     "EV235";
NETWORK
TITLE =SALITA ELEVATORE

      U(    ;
      O     "MSEL";
      O     ;
      U     "ASEL";
      U(    ;
      O     "BSA";
      O     "BA";
      )     ;
      )     ;
      U     "CSEL";
      =     "EV236";
NETWORK
TITLE =DISCESA ELEVATORE

      U(    ;
      U     "MDEL";
      O     ;
      U     "ADEL";
      U(    ;
      U     "BSA";
      O     "BA";
      )     ;
      )     ;
      U     "CDEL";
      =     "CDELE";

      U     "ELB";
      S     "MEB";

      U     "EV236";
      R     "MEB";

      U     "CDELE";
      UN    "PX283";
      O     ;
      U     "MEB";
      UN    "PX283";
      =     "EV237";
NETWORK
TITLE =DISCESA VASCA FLUSSAGGIO

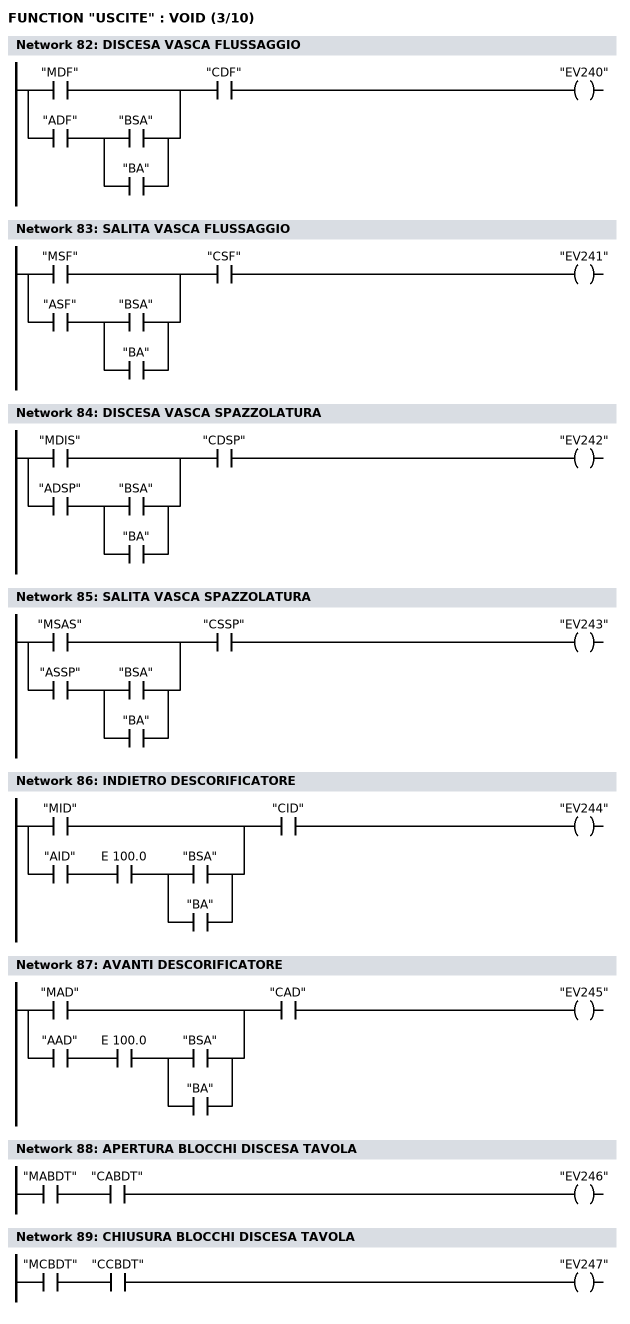
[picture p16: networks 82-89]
      U(    ;
      O     "MDF";
      O     ;
      U     "ADF";
      U(    ;
      O     "BSA";
      O     "BA";
      )     ;
      )     ;
      U     "CDF";
      =     "EV240";
NETWORK
TITLE =SALITA VASCA FLUSSAGGIO

      U(    ;
      O     "MSF";
      O     ;
      U     "ASF";
      U(    ;
      O     "BSA";
      O     "BA";
      )     ;
      )     ;
      U     "CSF";
      =     "EV241";
NETWORK
TITLE =DISCESA VASCA SPAZZOLATURA

      U(    ;
      O     "MDIS";
      O     ;
      U     "ADSP";
      U(    ;
      O     "BSA";
      O     "BA";
      )     ;
      )     ;
      U     "CDSP";
      =     "EV242";
NETWORK
TITLE =SALITA VASCA SPAZZOLATURA

      U(    ;
      O     "MSAS";
      O     ;
      U     "ASSP";
      U(    ;
      O     "BSA";
      O     "BA";
      )     ;
      )     ;
      U     "CSSP";
      =     "EV243";
NETWORK
TITLE =INDIETRO DESCORIFICATORE

      U(    ;
      O     "MID";
      O     ;
      U     "AID";
      U     E    100.0;
      U(    ;
      O     "BSA";
      O     "BA";
      )     ;
      )     ;
      U     "CID";
      =     "EV244";
NETWORK
TITLE =AVANTI DESCORIFICATORE

      U(    ;
      O     "MAD";
      O     ;
      U     "AAD";
      U     E    100.0;
      U(    ;
      O     "BSA";
      O     "BA";
      )     ;
      )     ;
      U     "CAD";
      =     "EV245";
NETWORK
TITLE =APERTURA BLOCCHI DISCESA TAVOLA

      U     "MABDT";
      U     "CABDT";
      =     "EV246";
NETWORK
TITLE =CHIUSURA BLOCCHI DISCESA TAVOLA

      U     "MCBDT";
      U     "CCBDT";
      =     "EV247";
NETWORK
TITLE =SALITA SPINTORI

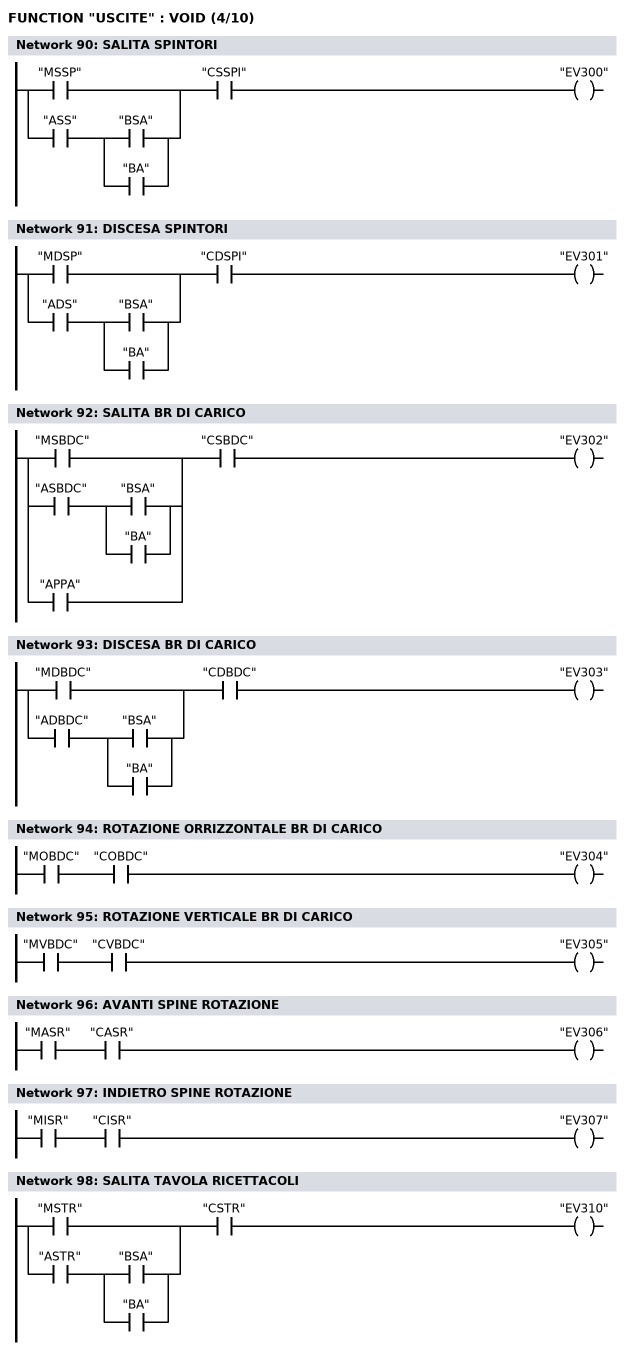
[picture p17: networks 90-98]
      U(    ;
      O     "MSSP";
      O     ;
      U     "ASS";
      U(    ;
      O     "BSA";
      O     "BA";
      )     ;
      )     ;
      U     "CSSPI";
      =     "EV300";
NETWORK
TITLE =DISCESA SPINTORI

      U(    ;
      O     "MDSP";
      O     ;
      U     "ADS";
      U(    ;
      O     "BSA";
      O     "BA";
      )     ;
      )     ;
      U     "CDSPI";
      =     "EV301";
NETWORK
TITLE =SALITA BR DI CARICO

      U(    ;
      O     "MSBDC";
      O     ;
      U     "ASBDC";
      U(    ;
      O     "BSA";
      O     "BA";
      )     ;
      O     "APPA";
      )     ;
      U     "CSBDC";
      =     "EV302";
NETWORK
TITLE =DISCESA BR DI CARICO

      U(    ;
      O     "MDBDC";
      O     ;
      U     "ADBDC";
      U(    ;
      O     "BSA";
      O     "BA";
      )     ;
      )     ;
      U     "CDBDC";
      =     "EV303";
NETWORK
TITLE =ROTAZIONE ORRIZZONTALE BR DI CARICO

      U     "MOBDC";
      U     "COBDC";
      =     "EV304";
NETWORK
TITLE =ROTAZIONE VERTICALE BR DI CARICO

      U     "MVBDC";
      U     "CVBDC";
      =     "EV305";
NETWORK
TITLE =AVANTI SPINE ROTAZIONE

      U     "MASR";
      U     "CASR";
      =     "EV306";
NETWORK
TITLE =INDIETRO SPINE ROTAZIONE

      U     "MISR";
      U     "CISR";
      =     "EV307";
NETWORK
TITLE =SALITA TAVOLA RICETTACOLI

      U(    ;
      O     "MSTR";
      O     ;
      U     "ASTR";
      U(    ;
      O     "BSA";
      O     "BA";
      )     ;
      )     ;
      U     "CSTR";
      =     "EV310";
NETWORK
TITLE =DISCESA TAVOLA RICETTACOLI

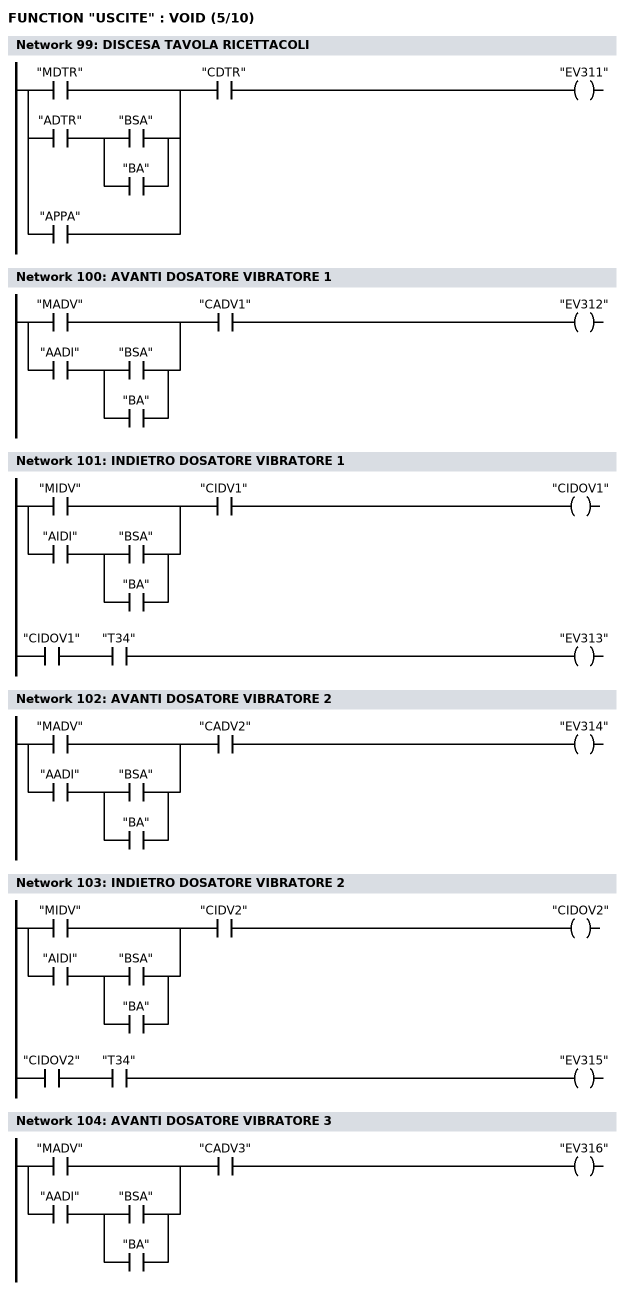
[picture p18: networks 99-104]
      U(    ;
      O     "MDTR";
      O     ;
      U     "ADTR";
      U(    ;
      O     "BSA";
      O     "BA";
      )     ;
      O     "APPA";
      )     ;
      U     "CDTR";
      =     "EV311";
NETWORK
TITLE =AVANTI DOSATORE VIBRATORE 1

      U(    ;
      O     "MADV";
      O     ;
      U     "AADI";
      U(    ;
      O     "BSA";
      O     "BA";
      )     ;
      )     ;
      U     "CADV1";
      =     "EV312";
NETWORK
TITLE =INDIETRO DOSATORE VIBRATORE 1

      U(    ;
      O     "MIDV";
      O     ;
      U     "AIDI";
      U(    ;
      O     "BSA";
      O     "BA";
      )     ;
      )     ;
      U     "CIDV1";
      =     "CIDOV1";

      U     "CIDOV1";
      U     "T34";
      =     "EV313";
NETWORK
TITLE =AVANTI DOSATORE VIBRATORE 2

      U(    ;
      O     "MADV";
      O     ;
      U     "AADI";
      U(    ;
      O     "BSA";
      O     "BA";
      )     ;
      )     ;
      U     "CADV2";
      =     "EV314";
NETWORK
TITLE =INDIETRO DOSATORE VIBRATORE 2

      U(    ;
      O     "MIDV";
      O     ;
      U     "AIDI";
      U(    ;
      O     "BSA";
      O     "BA";
      )     ;
      )     ;
      U     "CIDV2";
      =     "CIDOV2";

      U     "CIDOV2";
      U     "T34";
      =     "EV315";
NETWORK
TITLE =AVANTI DOSATORE VIBRATORE 3

      U(    ;
      O     "MADV";
      O     ;
      U     "AADI";
      U(    ;
      O     "BSA";
      O     "BA";
      )     ;
      )     ;
      U     "CADV3";
      =     "EV316";
NETWORK
TITLE =INDIETRO DOSATORE VIBRATORE 3

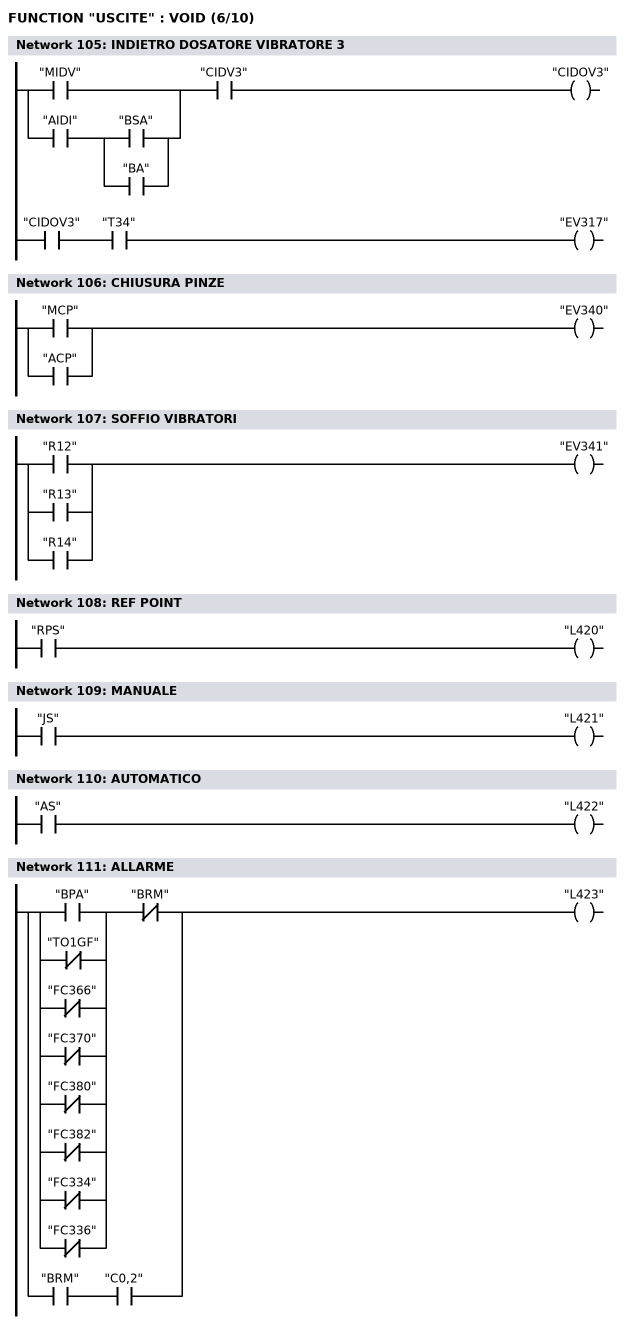
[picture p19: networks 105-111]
      U(    ;
      O     "MIDV";
      O     ;
      U     "AIDI";
      U(    ;
      O     "BSA";
      O     "BA";
      )     ;
      )     ;
      U     "CIDV3";
      =     "CIDOV3";

      U     "CIDOV3";
      U     "T34";
      =     "EV317";
NETWORK
TITLE =CHIUSURA PINZE

      O     "MCP";
      O     "ACP";
      =     "EV340";
NETWORK
TITLE =SOFFIO VIBRATORI

      O     "R12";
      O     "R13";
      O     "R14";
      =     "EV341";
NETWORK
TITLE =REF POINT

      U     "RPS";
      =     "L420";
NETWORK
TITLE =MANUALE

      U     "JS";
      =     "L421";
NETWORK
TITLE =AUTOMATICO

      U     "AS";
      =     "L422";
NETWORK
TITLE =ALLARME

      U(    ;
      O     "BPA";
      ON    "TO1GF";
      ON    "FC366";
      ON    "FC370";
      ON    "FC380";
      ON    "FC382";
      ON    "FC334";
      ON    "FC336";
      )     ;
      UN    "BRM";
      O     ;
      U     "BRM";
      U     "C0,2";
      =     "L423";
NETWORK
TITLE =PRENOTAZIONE APERTURA RIPARI (PULS ZONA VIBRATORI)

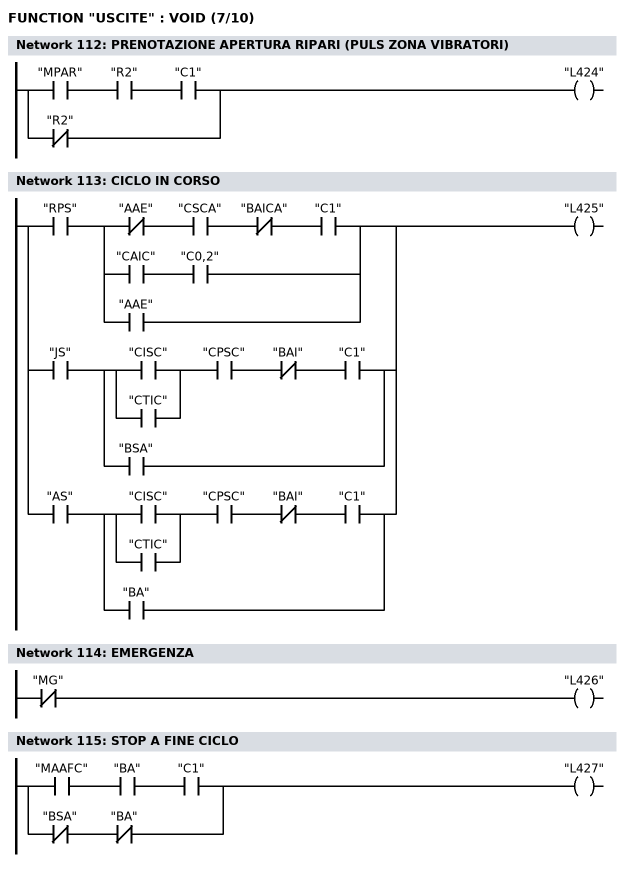
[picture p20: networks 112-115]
      U     "MPAR";
      U     "R2";
      U     "C1";
      ON    "R2";
      =     "L424";
NETWORK
TITLE =CICLO IN CORSO

      U     "RPS";
      U(    ;
      UN    "AAE";
      U     "CSCA";
      UN    "BAICA";
      U     "C1";
      O     ;
      U     "CAIC";
      U     "C0,2";
      O     "AAE";
      )     ;
      O     ;
      U     "JS";
      U(    ;
      U(    ;
      O     "CISC";
      O     "CTIC";
      )     ;
      U     "CPSC";
      UN    "BAI";
      U     "C1";
      O     "BSA";
      )     ;
      O     ;
      U     "AS";
      U(    ;
      U(    ;
      O     "CISC";
      O     "CTIC";
      )     ;
      U     "CPSC";
      UN    "BAI";
      U     "C1";
      O     "BA";
      )     ;
      =     "L425";
NETWORK
TITLE =EMERGENZA

      UN    "MG";
      =     "L426";
NETWORK
TITLE =STOP A FINE CICLO

      U     "MAAFC";
      U     "BA";
      U     "C1";
      O     ;
      UN    "BSA";
      UN    "BA";
      =     "L427";
NETWORK
TITLE =LAMPADA JOG + PULS VOLANTE

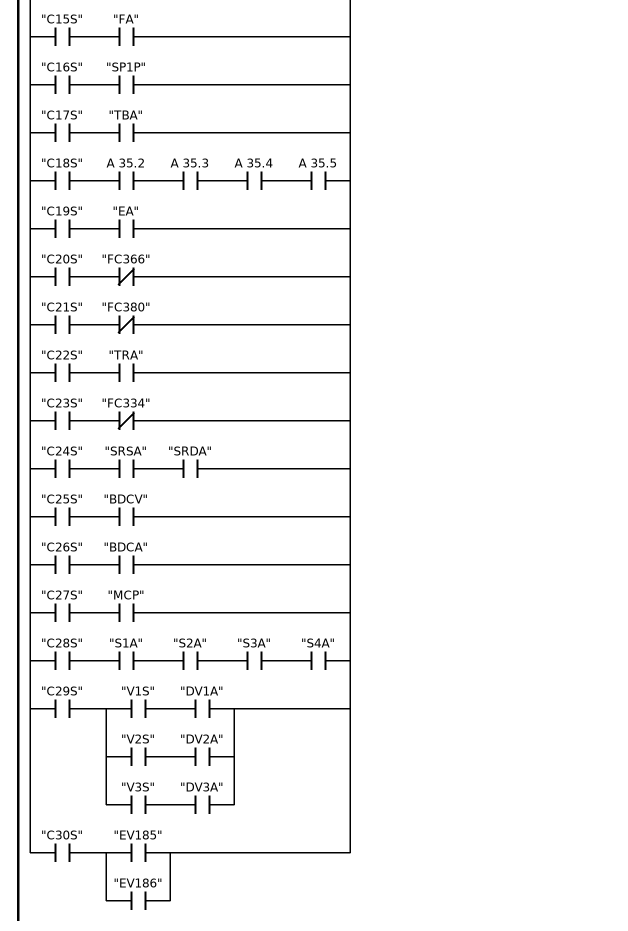
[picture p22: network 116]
      U     "C00S";
      U     "ELA";
      O     ;
      U     "C01S";
      U(    ;
      U     "S2IPDR";
      UN    "PX121";
      O     ;
      U     "S3IPDR";
      UN    "PX127";
      O     ;
      U     "S4IPDR";
      UN    "PX161";
      O     ;
      U     "S1IPDR";
      UN    "PX167";
      )     ;
      O     ;
      U     "C02S";
      U(    ;
      U     "S2IPDR";
      UN    "PX120";
      O     ;
      U     "S3IPDR";
      UN    "PX166";
      O     ;
      U     "S4IPDR";
      UN    "PX160";
      O     ;
      U     "S1IPDR";
      UN    "PX126";
      )     ;
      O     ;
      U     "C03S";
      U(    ;
      U     "S2IPDR";
      U     "RCS1A180G";
      O     ;
      U     "S3IPDR";
      U     "RCS2A180G";
      O     ;
      U     "S4IPDR";
      U     "RCS3A180G";
      O     ;
      U     "S1IPDR";
      U     "RCS4A180G";
      )     ;
      O     ;
      U     "C04S";
      U(    ;
      U     "S1IPDR";
      U     "RCS1A180G";
      O     ;
      U     "S2IPDR";
      U     "RCS2A180G";
      O     ;
      U     "S3IPDR";
      U     "RCS3A180G";
      O     ;
      U     "S4IPDR";
      U     "RCS4A180G";
      )     ;
      O     ;
      U     "C05S";
      U(    ;
      O     "TIPDM";
      O     "TIPDR";
      )     ;
      O     ;
      U     "C06S";
      U     "PX210";
      U     "SPIA";
      O     ;
      U     "C07S";
      U     "BDTC";
      O     ;
      U     "C08S";
      U     "R11";
      O     "C09S";
      O     ;
      U     "C10S";
      U     "SA";
      O     ;
      U     "C11S";
      U     "DA";
      O     ;
      U     "C12S";
      U     "STA";
      O     ;
      U     "C13S";
      U     "R10";
      O     "C14S";
      O     ;
      U     "C15S";
      U     "FA";
      O     ;
      U     "C16S";
      U     "SP1P";
      O     ;
      U     "C17S";
      U     "TBA";
      O     ;
      U     "C18S";
      U     A     35.2;
      U     A     35.3;
      U     A     35.4;
      U     A     35.5;
      O     ;
      U     "C19S";
      U     "EA";
      O     ;
      U     "C20S";
      UN    "FC366";
      O     ;
      U     "C21S";
      UN    "FC380";
      O     ;
      U     "C22S";
      U     "TRA";
      O     ;
      U     "C23S";
      UN    "FC334";
      O     ;
      U     "C24S";
      U     "SRSA";
      U     "SRDA";
      O     ;
      U     "C25S";
      U     "BDCV";
      O     ;
      U     "C26S";
      U     "BDCA";
      O     ;
      U     "C27S";
      U     "MCP";
      O     ;
      U     "C28S";
      U     "S1A";
      U     "S2A";
      U     "S3A";
      U     "S4A";
      O     ;
      U     "C29S";
      U(    ;
      U     "V1S";
      U     "DV1A";
      O     ;
      U     "V2S";
      U     "DV2A";
      O     ;
      U     "V3S";
      U     "DV3A";
      )     ;
      O     ;
      U     "C30S";
      U(    ;
      O     "EV185";
      O     "EV186";
      )     ;
      =     "LJ+";
NETWORK
TITLE =LAMPADA JOG - PULS VOLANTE

      U     "C00S";
      U     "ELB";
      O     ;
      U     "C01S";
      U(    ;
      U     "S2IPDR";
      U     "PX121";
      O     ;
      U     "S3IPDR";
      U     "PX127";
      O     ;
      U     "S4IPDR";
      U     "PX161";
      O     ;
      U     "S1IPDR";
      U     "PX167";
      )     ;
      O     ;
      U     "C02S";
      U(    ;
      U     "S2IPDR";
      U     "PX120";
      O     ;
      U     "S3IPDR";
      U     "PX166";
      O     ;
      U     "S4IPDR";
      U     "PX160";
      O     ;
      U     "S1IPDR";
      U     "PX126";
      )     ;
      O     ;
      U     "C03S";
      U(    ;
      U     "S2IPDR";
      U     "RCS1A0G";
      O     ;
      U     "S3IPDR";
      U     "RCS2A0G";
      O     ;
      U     "S4IPDR";
      U     "RCS3A0G";
      O     ;
      U     "S1IPDR";
      U     "RCS4A0G";
      )     ;
      O     ;
      U     "C04S";
      U(    ;
      U     "S1IPDR";
      U     "RCS1A0G";
      O     ;
      U     "S2IPDR";
      U     "RCS2A0G";
      O     ;
      U     "S3IPDR";
      U     "RCS3A0G";
      O     ;
      U     "S4IPDR";
      U     "RCS4A0G";
      )     ;
      O     ;
      U     "C05S";
      U(    ;
      O     "TIPDFC";
      O     "TIPDF";
      )     ;
      O     ;
      U     "C06S";
      U     "OFF";
      O     ;
      U     "C07S";
      U     "BDTA";
      O     ;
      U     "C08S";
      U     "OFF";
      O     "C09S";
      O     ;
      U     "C10S";
      U     "SI";
      O     ;
      U     "C11S";
      U     "DI";
      O     ;
      U     "C12S";
      U     "STB";
      O     ;
      U     "C13S";
      U     "OFF";
      O     "C14S";
      O     ;
      U     "C15S";
      U     "FI";
      O     ;
      U     "C16S";
      U     "OFF";
      O     ;
      U     "C17S";
      U     "TBI";
      O     ;
      U     "C18S";
      U     "OFF";
      O     ;
      U     "C19S";
      U     "EB";
      O     ;
      U     "C20S";
      UN    "FC370";
      O     ;
      U     "C21S";
      UN    "FC382";
      O     ;
      U     "C22S";
      U     "TRB";
      O     ;
      U     "C23S";
      UN    "FC336";
      O     ;
      U     "C24S";
      U     "SRSI";
      U     "SRDI";
      O     ;
      U     "C25S";
      U     "BDCO";
      O     ;
      U     "C26S";
      U(    ;
      U     "BDCI";
      U     "BDCBST";
      O     ;
      UN    "BDCI";
      U     "BDCBSS";
      )     ;
      O     ;
      U     "C27S";
      UN    "MCP";
      O     ;
      U     "C28S";
      U     "S1B";
      U     "S2B";
      U     "S3B";
      U     "S4B";
      O     ;
      U     "C29S";
      U(    ;
      U     "V1S";
      U     "DV1I";
      O     ;
      U     "V2S";
      U     "DV2I";
      O     ;
      U     "V3S";
      U     "DV3I";
      )     ;
      =     "LJ-";
NETWORK
TITLE =PRENOTAZIONE APERTURA RIPARI (PULS ZONA FORNO)

      U     "L424";
      =     "L432";
END_FUNCTION

